VERSION 5.8 ;
BUSBITCHARS "[]" ;
DIVIDERCHAR "/" ;
CLEARANCEMEASURE EUCLIDEAN ;

SITE coresite_DH_P
    SIZE 0.0450 BY 0.2880 ;
    CLASS CORE ;
    SYMMETRY X Y ;
END coresite_DH_P

SITE coresite_DH_N
    SIZE 0.0450 BY 0.2880 ;
    CLASS CORE ;
    SYMMETRY X Y ;
END coresite_DH_N

SITE coresite
    SIZE 0.0450 BY 0.1440 ;
    CLASS CORE ;
    SYMMETRY X Y ;
END coresite

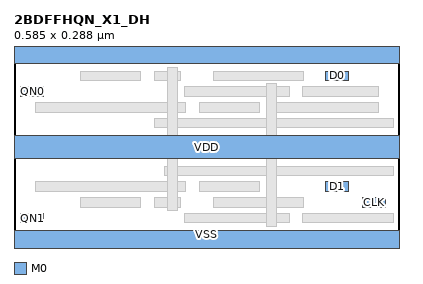
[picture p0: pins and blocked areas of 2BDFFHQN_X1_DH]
MACRO 2BDFFHQN_X1_DH
  CLASS CORE ;
  ORIGIN 0 0 ;
  FOREIGN 2BDFFHQN_X1_DH 0 0 ;
  SIZE 0.5850 BY 0.2880 ;
  SYMMETRY X Y ;
  SITE coresite_DH_N ;
  PIN D0
    DIRECTION INPUT ;
    USE SIGNAL ;
    PORT
      LAYER M0 ;
        RECT 0.4725 0.2590 0.5070 0.2450 ;
    END
  END D0
  PIN QN0
    DIRECTION OUTPUT ;
    USE SIGNAL ;
    PORT
      LAYER M0 ;
        RECT 0.0105 0.2350 0.0450 0.2210 ;
    END
  END QN0
  PIN CLK
    DIRECTION INPUT ;
    USE SIGNAL ;
    PORT
      LAYER M0 ;
        RECT 0.5280 0.0670 0.5625 0.0530 ;
    END
  END CLK
  PIN D1
    DIRECTION INPUT ;
    USE SIGNAL ;
    PORT
      LAYER M0 ;
        RECT 0.4725 0.0910 0.5070 0.0770 ;
    END
  END D1
  PIN QN1
    DIRECTION OUTPUT ;
    USE SIGNAL ;
    PORT
      LAYER M0 ;
        RECT 0.0105 0.0430 0.0450 0.0290 ;
    END
  END QN1
  PIN VDD
    DIRECTION INOUT ;
    USE POWER ;
    SHAPE ABUTMENT ;
    PORT
      LAYER M0 ;
        RECT 0.0000 0.1260 0.5850 0.1620 ;
    END
  END VDD
  PIN VSS
    DIRECTION INOUT ;
    USE GROUND ;
    SHAPE ABUTMENT ;
    PORT
      LAYER M0 ;
        RECT 0.0000 0.2700 0.5850 0.3060 ;
        RECT 0.0000 -0.0180 0.5850 0.0180 ;
    END
  END VSS
  OBS
      LAYER V0 ;
        RECT 0.3830 0.1730 0.3970 0.1870 ;
        RECT 0.3830 0.2210 0.3970 0.2350 ;
        RECT 0.3830 0.0290 0.3970 0.0430 ;
        RECT 0.2330 0.2450 0.2470 0.2590 ;
        RECT 0.2330 0.0530 0.2470 0.0670 ;
        RECT 0.2330 0.1010 0.2470 0.1150 ;
      LAYER M0 ;
        RECT 0.3030 0.2450 0.4395 0.2590 ;
        RECT 0.2130 0.2450 0.2520 0.2590 ;
        RECT 0.1005 0.2450 0.1920 0.2590 ;
        RECT 0.4380 0.2210 0.5520 0.2350 ;
        RECT 0.2580 0.2210 0.4170 0.2350 ;
        RECT 0.3930 0.1970 0.5520 0.2110 ;
        RECT 0.2805 0.1970 0.3720 0.2110 ;
        RECT 0.0330 0.1970 0.2595 0.2110 ;
        RECT 0.2130 0.1730 0.5745 0.1870 ;
        RECT 0.2280 0.1010 0.5745 0.1150 ;
        RECT 0.2805 0.0770 0.3720 0.0910 ;
        RECT 0.0330 0.0770 0.2595 0.0910 ;
        RECT 0.3030 0.0530 0.4395 0.0670 ;
        RECT 0.2130 0.0530 0.2520 0.0670 ;
        RECT 0.1005 0.0530 0.1920 0.0670 ;
        RECT 0.4380 0.0290 0.5745 0.0430 ;
        RECT 0.2580 0.0290 0.4170 0.0430 ;
      LAYER M1 ;
        RECT 0.2325 0.2640 0.2475 0.0480 ;
        RECT 0.3825 0.2400 0.3975 0.0240 ;
  END
END 2BDFFHQN_X1_DH

END LIBRARY
